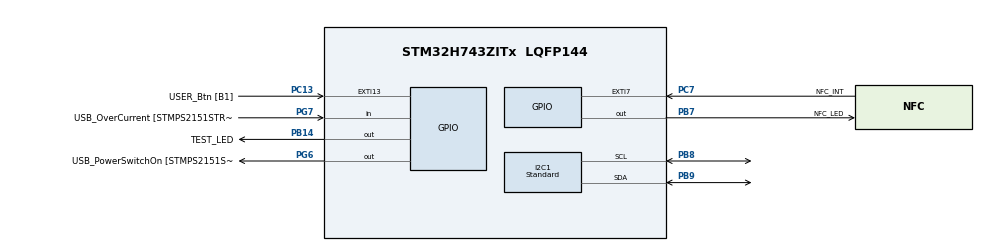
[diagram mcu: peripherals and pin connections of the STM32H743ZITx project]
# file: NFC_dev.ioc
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I2C1.I2C_Speed_Mode=I2C_Standard
I2C1.Timing=0x10C0ECFF
Mcu.Family=STM32H7
Mcu.Name=STM32H743ZITx
Mcu.Package=LQFP144
NVIC.EXTI9_5_IRQn=true\:0\:0\:false\:false\:true\:true\:true
NVIC.PriorityGroup=NVIC_PRIORITYGROUP_4
PA1.GPIO_Label=RMII_REF_CLK
PA1.Signal=ETH_REF_CLK
PA10.GPIO_Label=USB_ID
PA10.Signal=USB_OTG_FS_ID
PA11.GPIO_Label=USB_DM
PA11.Signal=USB_OTG_FS_DM
PA12.GPIO_Label=USB_DP
PA12.Signal=USB_OTG_FS_DP
PA2.GPIO_Label=RMII_MDIO
PA2.Signal=ETH_MDIO
PA7.GPIO_Label=RMII_CRS_DV
PA7.Signal=ETH_CRS_DV
PA8.GPIO_Label=USB_SOF [TP1]
PA8.Signal=USB_OTG_FS_SOF
PA9.GPIO_Label=USB_VBUS
PA9.Signal=USB_OTG_FS_VBUS
PB13.GPIO_Label=RMII_TXD1
PB13.Signal=ETH_TXD1
PB14.GPIO_Label=TEST_LED
PB14.Signal=GPIO_Output
PB7.GPIO_Label=NFC_LED
PB7.Signal=GPIO_Output
PB8.GPIO_Pu=GPIO_PULLUP
PB8.Mode=I2C
PB8.Signal=I2C1_SCL
PB9.GPIO_Pu=GPIO_PULLUP
PB9.Mode=I2C
PB9.Signal=I2C1_SDA
PC1.GPIO_Label=RMII_MDC
PC1.Signal=ETH_MDC
PC13.GPIO_Label=USER_Btn [B1]
PC13.Signal=GPXTI13
PC14-OSC32_IN\ (OSC32_IN).Signal=RCC_OSC32_IN
PC15-OSC32_OUT\ (OSC32_OUT).Signal=RCC_OSC32_OUT
PC4.GPIO_Label=RMII_RXD0
PC4.Signal=ETH_RXD0
PC5.GPIO_Label=RMII_RXD1
PC5.Signal=ETH_RXD1
PC7.GPIO_Label=NFC_INT
PC7.Signal=GPXTI7
PD8.GPIO_Label=STLK_RX [STM32F103CBT6_PA3]
PD8.Signal=USART3_TX
PD9.GPIO_Label=STLK_TX [STM32F103CBT6_PA2]
PD9.Signal=USART3_RX
PG11.GPIO_Label=RMII_TX_EN
PG11.Signal=ETH_TX_EN
PG13.GPIO_Label=RMII_TXD0
PG13.Signal=ETH_TXD0
PG6.GPIO_Label=USB_PowerSwitchOn [STMPS2151STR_EN]
PG6.Signal=GPIO_Output
PG7.GPIO_Label=USB_OverCurrent [STMPS2151STR_FAULT]
PG7.Signal=GPIO_Input
PH0-OSC_IN\ (PH0).GPIO_Label=MCO
PH0-OSC_IN\ (PH0).Mode=HSE-External-Clock-Source
PH0-OSC_IN\ (PH0).Signal=RCC_OSC_IN
ProjectManager.HeapSize=0x200
ProjectManager.StackSize=0x400
ProjectManager.TargetToolchain=STM32CubeIDE
RCC.48MHZClocksFreq_Value=24000000
RCC.ADCFreq_Value=16125000
RCC.AHBFreq_Value=216000000
RCC.APB1CLKDivider=RCC_HCLK_DIV4
RCC.APB1Freq_Value=100000000
RCC.APB1TimFreq_Value=108000000
RCC.APB2CLKDivider=RCC_HCLK_DIV2
RCC.APB2Freq_Value=100000000
RCC.APB2TimFreq_Value=216000000
RCC.APB3Freq_Value=100000000
RCC.APB4Freq_Value=100000000
RCC.CortexFreq_Value=400000000
RCC.D1PPRE=RCC_APB3_DIV2
RCC.D2PPRE1=RCC_APB1_DIV2
RCC.D2PPRE2=RCC_APB2_DIV2
RCC.D3PPRE=RCC_APB4_DIV2
RCC.DIVM1=1
RCC.DIVN1=100
RCC.DIVQ1=4
RCC.HCLKFreq_Value=200000000
RCC.HPRE=RCC_HCLK_DIV2
RCC.HSE_VALUE=8000000
RCC.HSI_VALUE=64000000
RCC.PLLFRACN=0
RCC.PLLM=25
RCC.PLLMUL=RCC_PLL_MUL9
RCC.PLLN=432
RCC.PLLQ=9
RCC.PLLSourceVirtual=RCC_PLLSOURCE_HSE
RCC.PRESCALERUSB=RCC_USBCLKSOURCE_PLL_DIV1_5
RCC.PWR_Regulator_Voltage_Scale=PWR_REGULATOR_VOLTAGE_SCALE1
RCC.SYSCLKFreq_VALUE=400000000
RCC.SYSCLKSource=RCC_SYSCLKSOURCE_PLLCLK
RCC.SYSCLKSourceVirtual=RCC_SYSCLKSOURCE_PLLCLK
RCC.USBFreq_Value=200000000
RCC.VCOOutputFreq_Value=432000000
board=NUCLEO-H743ZI

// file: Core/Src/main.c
/* USER CODE BEGIN Header */
/**
  ******************************************************************************
  * @file           : main.c
  * @brief          : Main program body
  ******************************************************************************
  * @attention
  *
  * Copyright (c) 2022 STMicroelectronics.
  * All rights reserved.
  *
  * This software is licensed under terms that can be found in the LICENSE file
  * in the root directory of this software component.
  * If no LICENSE file comes with this software, it is provided AS-IS.
  *
  ******************************************************************************
  */
/* USER CODE END Header */
#include "main.h"
#include "i2c.h"
#include "gpio.h"

/* USER CODE BEGIN Includes */
#include "pn532.h"
/* USER CODE END Includes */

/* USER CODE BEGIN PV */
uint8_t pn532_rx_data[64];
uint8_t pn532_fw_version[6];
uint8_t pn532_int_flag;
uint8_t rx_data_size;
/* USER CODE END PV */

void SystemClock_Config(void);

int main(void)
{

  /* MCU Configuration--------------------------------------------------------*/

  /* Reset of all peripherals, Initializes the Flash interface and the Systick. */
  HAL_Init();

  /* Configure the system clock */
  SystemClock_Config();

  /* Initialize all configured peripherals */
  MX_GPIO_Init();
  MX_I2C1_Init();
  /* USER CODE BEGIN 2 */
  rx_data_size = get_firmware_version();
  /* USER CODE END 2 */

  /* Infinite loop */
  /* USER CODE BEGIN WHILE */
  while (1)
  {

//	  if (pn532_int_flag){
//		  read_pn532_data(pn532_rx_data, 64);
//		  pn532_int_flag = 0;
//	  }
    /* USER CODE END WHILE */

  }
}

void SystemClock_Config(void)
{
  RCC_OscInitTypeDef RCC_OscInitStruct = {0};
  RCC_ClkInitTypeDef RCC_ClkInitStruct = {0};

  /** Supply configuration update enable
  */
  HAL_PWREx_ConfigSupply(PWR_LDO_SUPPLY);
  /** Configure the main internal regulator output voltage
  */
  __HAL_PWR_VOLTAGESCALING_CONFIG(PWR_REGULATOR_VOLTAGE_SCALE1);

  while(!__HAL_PWR_GET_FLAG(PWR_FLAG_VOSRDY)) {}
  /** Initializes the RCC Oscillators according to the specified parameters
  * in the RCC_OscInitTypeDef structure.
  */
  RCC_OscInitStruct.OscillatorType = RCC_OSCILLATORTYPE_HSI;
  RCC_OscInitStruct.HSIState = RCC_HSI_DIV1;
  RCC_OscInitStruct.HSICalibrationValue = RCC_HSICALIBRATION_DEFAULT;
  RCC_OscInitStruct.PLL.PLLState = RCC_PLL_ON;
  RCC_OscInitStruct.PLL.PLLSource = RCC_PLLSOURCE_HSI;
  RCC_OscInitStruct.PLL.PLLM = 4;
  RCC_OscInitStruct.PLL.PLLN = 10;
  RCC_OscInitStruct.PLL.PLLP = 2;
  RCC_OscInitStruct.PLL.PLLQ = 4;
  RCC_OscInitStruct.PLL.PLLR = 2;
  RCC_OscInitStruct.PLL.PLLRGE = RCC_PLL1VCIRANGE_3;
  RCC_OscInitStruct.PLL.PLLVCOSEL = RCC_PLL1VCOMEDIUM;
  RCC_OscInitStruct.PLL.PLLFRACN = 0;
  if (HAL_RCC_OscConfig(&RCC_OscInitStruct) != HAL_OK)
  {
    Error_Handler();
  }
  /** Initializes the CPU, AHB and APB buses clocks
  */
  RCC_ClkInitStruct.ClockType = RCC_CLOCKTYPE_HCLK|RCC_CLOCKTYPE_SYSCLK
                              |RCC_CLOCKTYPE_PCLK1|RCC_CLOCKTYPE_PCLK2
                              |RCC_CLOCKTYPE_D3PCLK1|RCC_CLOCKTYPE_D1PCLK1;
  RCC_ClkInitStruct.SYSCLKSource = RCC_SYSCLKSOURCE_PLLCLK;
  RCC_ClkInitStruct.SYSCLKDivider = RCC_SYSCLK_DIV1;
  RCC_ClkInitStruct.AHBCLKDivider = RCC_HCLK_DIV1;
  RCC_ClkInitStruct.APB3CLKDivider = RCC_APB3_DIV1;
  RCC_ClkInitStruct.APB1CLKDivider = RCC_APB1_DIV1;
  RCC_ClkInitStruct.APB2CLKDivider = RCC_APB2_DIV1;
  RCC_ClkInitStruct.APB4CLKDivider = RCC_APB4_DIV1;

  if (HAL_RCC_ClockConfig(&RCC_ClkInitStruct, FLASH_LATENCY_1) != HAL_OK)
  {
    Error_Handler();
  }
}

void Error_Handler(void)
{
  /* USER CODE BEGIN Error_Handler_Debug */
  /* User can add his own implementation to report the HAL error return state */
  __disable_irq();
  while (1)
  {
	  HAL_GPIO_WritePin(TEST_LED_GPIO_Port, TEST_LED_Pin, GPIO_PIN_SET);
	  HAL_Delay(1000);
	  HAL_GPIO_WritePin(TEST_LED_GPIO_Port, TEST_LED_Pin, GPIO_PIN_RESET);
	  HAL_Delay(1000);
  }
  /* USER CODE END Error_Handler_Debug */
}
